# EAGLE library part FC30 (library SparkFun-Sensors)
STMicro 3-axis accelerometer with tap detection- orientation output only.

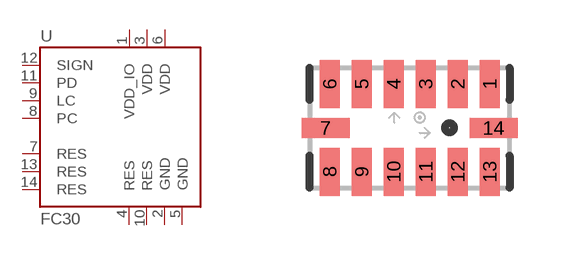
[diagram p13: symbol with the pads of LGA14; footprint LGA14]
Designator prefix -

## FC30SMD  [LGA14]
1  VDD_IO  pwr
2  GND  pwr
3  VDD  pwr
4  RES  pwr
5  GND  pwr
6  VDD  pwr
7  RES  nc
8  PC  out
9  LC  out
10  RES  pwr
11  PD  in
12  SIGN  out
13  RES  nc
14  RES  nc

## Footprint LGA14 (pad centres in mm)
smd 0.5 x 1.2: 1 2,1.1; 2 1.2,1.1; 3 0.4,1.1; 4 -0.4,1.1; 5 -1.2,1.1; 6 -2,1.1; 8 -2,-1.1; 9 -1.2,-1.1; 10 -0.4,-1.1; 11 0.4,-1.1; 12 1.2,-1.1; 13 2,-1.1
smd 1.2 x 0.5: 7 -2.1,0; 14 2.1,0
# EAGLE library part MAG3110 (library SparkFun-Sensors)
3-axis digital (I2C) magnetometer

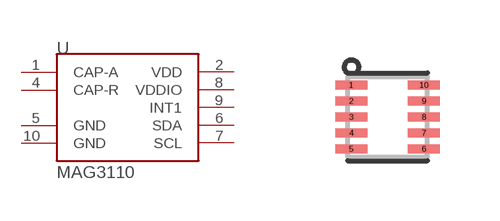
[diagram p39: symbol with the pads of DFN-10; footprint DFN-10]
Designator prefix U

## MAG3110  [DFN-10]
1  CAP-A
2  VDD
4  CAP-R
5  GND
6  SDA
7  SCL
8  VDDIO
9  INT1
10  GND

## Footprint DFN-10 (pad centres in mm)
10-pin DFN, 2mm x 2mm x 0.85mm
smd 0.8 x 0.22: 1 -0.91,0.8; 2 -0.91,0.4; 3 -0.91,0; 4 -0.91,-0.4; 5 -0.91,-0.8; 6 0.91,-0.8; 7 0.91,-0.4; 8 0.91,0; 9 0.91,0.4; 10 0.91,0.8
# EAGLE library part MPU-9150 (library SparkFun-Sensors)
9DOF (3mag, 3accel, 3rotat). I2C interface.

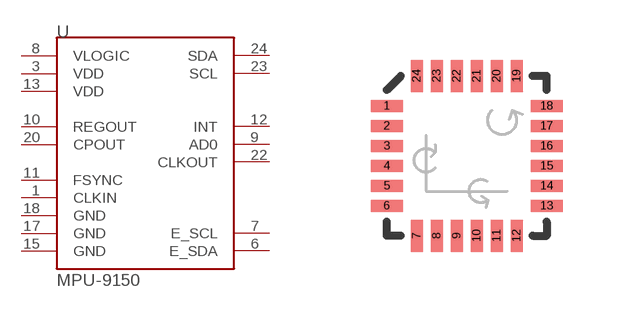
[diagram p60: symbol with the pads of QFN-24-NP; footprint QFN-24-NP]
Designator prefix U

## MPU-9150QFN-24-NP  [QFN-24-NP]
1  CLKIN
3  VDD
6  E_SDA
7  E_SCL
8  VLOGIC
9  AD0
10  REGOUT
11  FSYNC
12  INT
13  VDD
15  GND
17  GND
18  GND
20  CPOUT
22  CLKOUT
23  SCL
24  SDA

## Footprint QFN-24-NP (pad centres in mm)
smd 0.8 x 0.3: 1 -2,1.25; 2 -2,0.75; 3 -2,0.25; 4 -2,-0.25; 5 -2,-0.75; 6 -2,-1.25; 13 2,-1.25; 14 2,-0.75; 15 2,-0.25; 16 2,0.25; 17 2,0.75; 18 2,1.25
smd 0.3 x 0.8: 7 -1.25,-2; 8 -0.75,-2; 9 -0.25,-2; 10 0.25,-2; 11 0.75,-2; 12 1.25,-2; 19 1.25,2; 20 0.75,2; 21 0.25,2; 22 -0.25,2; 23 -0.75,2; 24 -1.25,2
